VERSION 5.7 ;
  NOWIREEXTENSIONATPIN ON ;
  DIVIDERCHAR "/" ;
  BUSBITCHARS "[]" ;
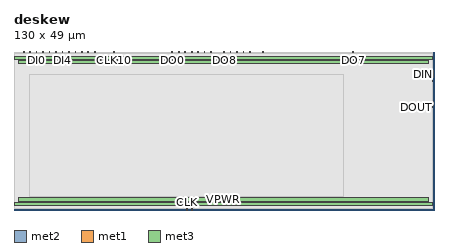
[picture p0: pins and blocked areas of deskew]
MACRO deskew
  CLASS BLOCK ;
  FOREIGN deskew ;
  ORIGIN 0.000 0.000 ;
  SIZE 130.000 BY 49.000 ;
  PIN CLK
    DIRECTION INPUT ;
    USE SIGNAL ;
    ANTENNAGATEAREA 0.852000 ;
    PORT
      LAYER met2 ;
        RECT 53.350 0.000 53.650 1.000 ;
    END
  END CLK
  PIN CLK10
    DIRECTION OUTPUT ;
    USE SIGNAL ;
    ANTENNAGATEAREA 0.852000 ;
    ANTENNADIFFAREA 0.445500 ;
    PORT
      LAYER met2 ;
        RECT 30.900 48.600 31.100 49.000 ;
    END
  END CLK10
  PIN DI0
    DIRECTION OUTPUT ;
    USE SIGNAL ;
    ANTENNAGATEAREA 0.247500 ;
    ANTENNADIFFAREA 0.445500 ;
    PORT
      LAYER met2 ;
        RECT 6.900 48.600 7.100 49.000 ;
    END
  END DI0
  PIN DI1
    DIRECTION OUTPUT ;
    USE SIGNAL ;
    ANTENNAGATEAREA 0.247500 ;
    ANTENNADIFFAREA 0.445500 ;
    PORT
      LAYER met2 ;
        RECT 8.900 48.600 9.100 49.000 ;
    END
  END DI1
  PIN DI2
    DIRECTION OUTPUT ;
    USE SIGNAL ;
    ANTENNAGATEAREA 0.247500 ;
    ANTENNADIFFAREA 0.445500 ;
    PORT
      LAYER met2 ;
        RECT 10.900 48.600 11.100 49.000 ;
    END
  END DI2
  PIN DI3
    DIRECTION OUTPUT ;
    USE SIGNAL ;
    ANTENNAGATEAREA 0.247500 ;
    ANTENNADIFFAREA 0.445500 ;
    PORT
      LAYER met2 ;
        RECT 12.900 48.600 13.100 49.000 ;
    END
  END DI3
  PIN DI4
    DIRECTION OUTPUT ;
    USE SIGNAL ;
    ANTENNAGATEAREA 0.247500 ;
    ANTENNADIFFAREA 0.445500 ;
    PORT
      LAYER met2 ;
        RECT 14.900 48.600 15.100 49.000 ;
    END
  END DI4
  PIN DI5
    DIRECTION OUTPUT ;
    USE SIGNAL ;
    ANTENNAGATEAREA 0.247500 ;
    ANTENNADIFFAREA 0.445500 ;
    PORT
      LAYER met2 ;
        RECT 16.900 48.600 17.100 49.000 ;
    END
  END DI5
  PIN DI6
    DIRECTION OUTPUT ;
    USE SIGNAL ;
    ANTENNAGATEAREA 0.247500 ;
    ANTENNADIFFAREA 0.445500 ;
    PORT
      LAYER met2 ;
        RECT 18.900 48.600 19.100 49.000 ;
    END
  END DI6
  PIN DI7
    DIRECTION OUTPUT ;
    USE SIGNAL ;
    ANTENNAGATEAREA 0.247500 ;
    ANTENNADIFFAREA 0.445500 ;
    PORT
      LAYER met2 ;
        RECT 20.900 48.600 21.100 49.000 ;
    END
  END DI7
  PIN DI8
    DIRECTION OUTPUT ;
    USE SIGNAL ;
    ANTENNAGATEAREA 0.247500 ;
    ANTENNADIFFAREA 0.445500 ;
    PORT
      LAYER met2 ;
        RECT 22.900 48.600 23.100 49.000 ;
    END
  END DI8
  PIN DI9
    DIRECTION OUTPUT ;
    USE SIGNAL ;
    ANTENNAGATEAREA 0.247500 ;
    ANTENNADIFFAREA 0.445500 ;
    PORT
      LAYER met2 ;
        RECT 24.900 48.600 25.100 49.000 ;
    END
  END DI9
  PIN DIN
    DIRECTION INPUT ;
    USE SIGNAL ;
    ANTENNAGATEAREA 0.213000 ;
    PORT
      LAYER met1 ;
        RECT 129.400 41.800 129.600 42.200 ;
    END
  END DIN
  PIN DO0
    DIRECTION INPUT ;
    USE SIGNAL ;
    ANTENNAGATEAREA 0.213000 ;
    PORT
      LAYER met2 ;
        RECT 48.900 48.600 49.100 49.000 ;
    END
  END DO0
  PIN DO1
    DIRECTION INPUT ;
    USE SIGNAL ;
    ANTENNAGATEAREA 0.213000 ;
    PORT
      LAYER met2 ;
        RECT 50.900 48.600 51.100 49.000 ;
    END
  END DO1
  PIN DO2
    DIRECTION INPUT ;
    USE SIGNAL ;
    ANTENNAGATEAREA 0.213000 ;
    PORT
      LAYER met2 ;
        RECT 52.900 48.600 53.100 49.000 ;
    END
  END DO2
  PIN DO3
    DIRECTION INPUT ;
    USE SIGNAL ;
    ANTENNAGATEAREA 0.213000 ;
    PORT
      LAYER met2 ;
        RECT 54.900 48.600 55.100 49.000 ;
    END
  END DO3
  PIN DO4
    DIRECTION INPUT ;
    USE SIGNAL ;
    ANTENNAGATEAREA 0.213000 ;
    PORT
      LAYER met2 ;
        RECT 56.900 48.600 57.100 49.000 ;
    END
  END DO4
  PIN DO5
    DIRECTION INPUT ;
    USE SIGNAL ;
    ANTENNAGATEAREA 0.213000 ;
    PORT
      LAYER met2 ;
        RECT 58.900 48.600 59.100 49.000 ;
    END
  END DO5
  PIN DO6
    DIRECTION INPUT ;
    USE SIGNAL ;
    ANTENNAGATEAREA 0.213000 ;
    PORT
      LAYER met2 ;
        RECT 60.900 48.600 61.100 49.000 ;
    END
  END DO6
  PIN DO7
    DIRECTION INPUT ;
    USE SIGNAL ;
    ANTENNAGATEAREA 0.213000 ;
    PORT
      LAYER met2 ;
        RECT 104.900 48.600 105.100 49.000 ;
    END
  END DO7
  PIN DO8
    DIRECTION INPUT ;
    USE SIGNAL ;
    ANTENNAGATEAREA 0.213000 ;
    PORT
      LAYER met2 ;
        RECT 64.900 48.600 65.100 49.000 ;
    END
  END DO8
  PIN DO9
    DIRECTION INPUT ;
    USE SIGNAL ;
    ANTENNAGATEAREA 0.213000 ;
    PORT
      LAYER met2 ;
        RECT 66.900 48.600 67.100 49.000 ;
    END
  END DO9
  PIN DOUT
    DIRECTION OUTPUT ;
    USE SIGNAL ;
    ANTENNADIFFAREA 0.445500 ;
    PORT
      LAYER met1 ;
        RECT 129.400 31.600 129.600 32.000 ;
    END
  END DOUT
  PIN RESET_N
    DIRECTION INPUT ;
    USE SIGNAL ;
    ANTENNAGATEAREA 0.213000 ;
    PORT
      LAYER met2 ;
        RECT 55.050 0.000 55.350 1.000 ;
    END
  END RESET_N
  PIN RESET_OUT_N
    DIRECTION OUTPUT ;
    USE SIGNAL ;
    ANTENNAGATEAREA 0.495000 ;
    ANTENNADIFFAREA 0.445500 ;
    PORT
      LAYER met2 ;
        RECT 72.900 48.600 73.100 49.000 ;
    END
  END RESET_OUT_N
  PIN RESTART
    DIRECTION INPUT ;
    USE SIGNAL ;
    ANTENNAGATEAREA 0.213000 ;
    PORT
      LAYER met2 ;
        RECT 76.900 48.600 77.100 49.000 ;
    END
  END RESTART
  PIN REV
    DIRECTION INPUT ;
    USE SIGNAL ;
    ANTENNAGATEAREA 0.213000 ;
    PORT
      LAYER met1 ;
        RECT 129.400 39.800 129.600 40.200 ;
    END
  END REV
  PIN SYNCED
    DIRECTION OUTPUT ;
    USE SIGNAL ;
    ANTENNAGATEAREA 1.485000 ;
    ANTENNADIFFAREA 0.445500 ;
    PORT
      LAYER met2 ;
        RECT 2.900 48.600 3.100 49.000 ;
    END
  END SYNCED
  PIN SYNCING
    DIRECTION OUTPUT ;
    USE SIGNAL ;
    ANTENNAGATEAREA 0.990000 ;
    ANTENNADIFFAREA 0.445500 ;
    PORT
      LAYER met2 ;
        RECT 4.900 48.600 5.100 49.000 ;
    END
  END SYNCING
  PIN VGND
    DIRECTION INOUT ;
    USE GROUND ;
    PORT
      LAYER met3 ;
        RECT 0.160 1.420 129.560 2.420 ;
    END
    PORT
      LAYER met3 ;
        RECT 0.160 46.540 129.560 47.540 ;
    END
  END VGND
  PIN VPWR
    DIRECTION INOUT ;
    USE POWER ;
    PORT
      LAYER met3 ;
        RECT 1.460 2.720 128.260 3.720 ;
    END
    PORT
      LAYER met3 ;
        RECT 1.460 45.240 128.260 46.240 ;
    END
  END VPWR
  PIN XMT_RD
    DIRECTION INPUT ;
    USE SIGNAL ;
    ANTENNAGATEAREA 0.213000 ;
    PORT
      LAYER met2 ;
        RECT 70.900 48.600 71.100 49.000 ;
    END
  END XMT_RD
  PIN XMT_READY
    DIRECTION INPUT ;
    USE SIGNAL ;
    ANTENNAGATEAREA 0.213000 ;
    PORT
      LAYER met2 ;
        RECT 68.900 48.600 69.100 49.000 ;
    END
  END XMT_READY
  OBS
      LAYER nwell ;
        RECT 0.270 2.635 129.450 46.325 ;
      LAYER li1 ;
        RECT 0.460 2.635 129.260 46.325 ;
      LAYER met1 ;
        RECT 0.160 42.480 129.560 48.580 ;
        RECT 0.160 41.520 129.120 42.480 ;
        RECT 0.160 40.480 129.560 41.520 ;
        RECT 0.160 39.520 129.120 40.480 ;
        RECT 0.160 32.280 129.560 39.520 ;
        RECT 0.160 31.320 129.120 32.280 ;
        RECT 0.160 0.720 129.560 31.320 ;
      LAYER met2 ;
        RECT 0.160 48.320 2.620 48.610 ;
        RECT 3.380 48.320 4.620 48.610 ;
        RECT 5.380 48.320 6.620 48.610 ;
        RECT 7.380 48.320 8.620 48.610 ;
        RECT 9.380 48.320 10.620 48.610 ;
        RECT 11.380 48.320 12.620 48.610 ;
        RECT 13.380 48.320 14.620 48.610 ;
        RECT 15.380 48.320 16.620 48.610 ;
        RECT 17.380 48.320 18.620 48.610 ;
        RECT 19.380 48.320 20.620 48.610 ;
        RECT 21.380 48.320 22.620 48.610 ;
        RECT 23.380 48.320 24.620 48.610 ;
        RECT 25.380 48.320 30.620 48.610 ;
        RECT 31.380 48.320 48.620 48.610 ;
        RECT 49.380 48.320 50.620 48.610 ;
        RECT 51.380 48.320 52.620 48.610 ;
        RECT 53.380 48.320 54.620 48.610 ;
        RECT 55.380 48.320 56.620 48.610 ;
        RECT 57.380 48.320 58.620 48.610 ;
        RECT 59.380 48.320 60.620 48.610 ;
        RECT 61.380 48.320 64.620 48.610 ;
        RECT 65.380 48.320 66.620 48.610 ;
        RECT 67.380 48.320 68.620 48.610 ;
        RECT 69.380 48.320 70.620 48.610 ;
        RECT 71.380 48.320 72.620 48.610 ;
        RECT 73.380 48.320 76.620 48.610 ;
        RECT 77.380 48.320 104.620 48.610 ;
        RECT 105.380 48.320 129.560 48.610 ;
        RECT 0.160 1.280 129.560 48.320 ;
        RECT 0.160 0.340 53.070 1.280 ;
        RECT 53.930 0.340 54.770 1.280 ;
        RECT 55.630 0.340 129.560 1.280 ;
      LAYER met3 ;
        RECT 4.665 4.255 102.055 41.985 ;
  END
END deskew
END LIBRARY

